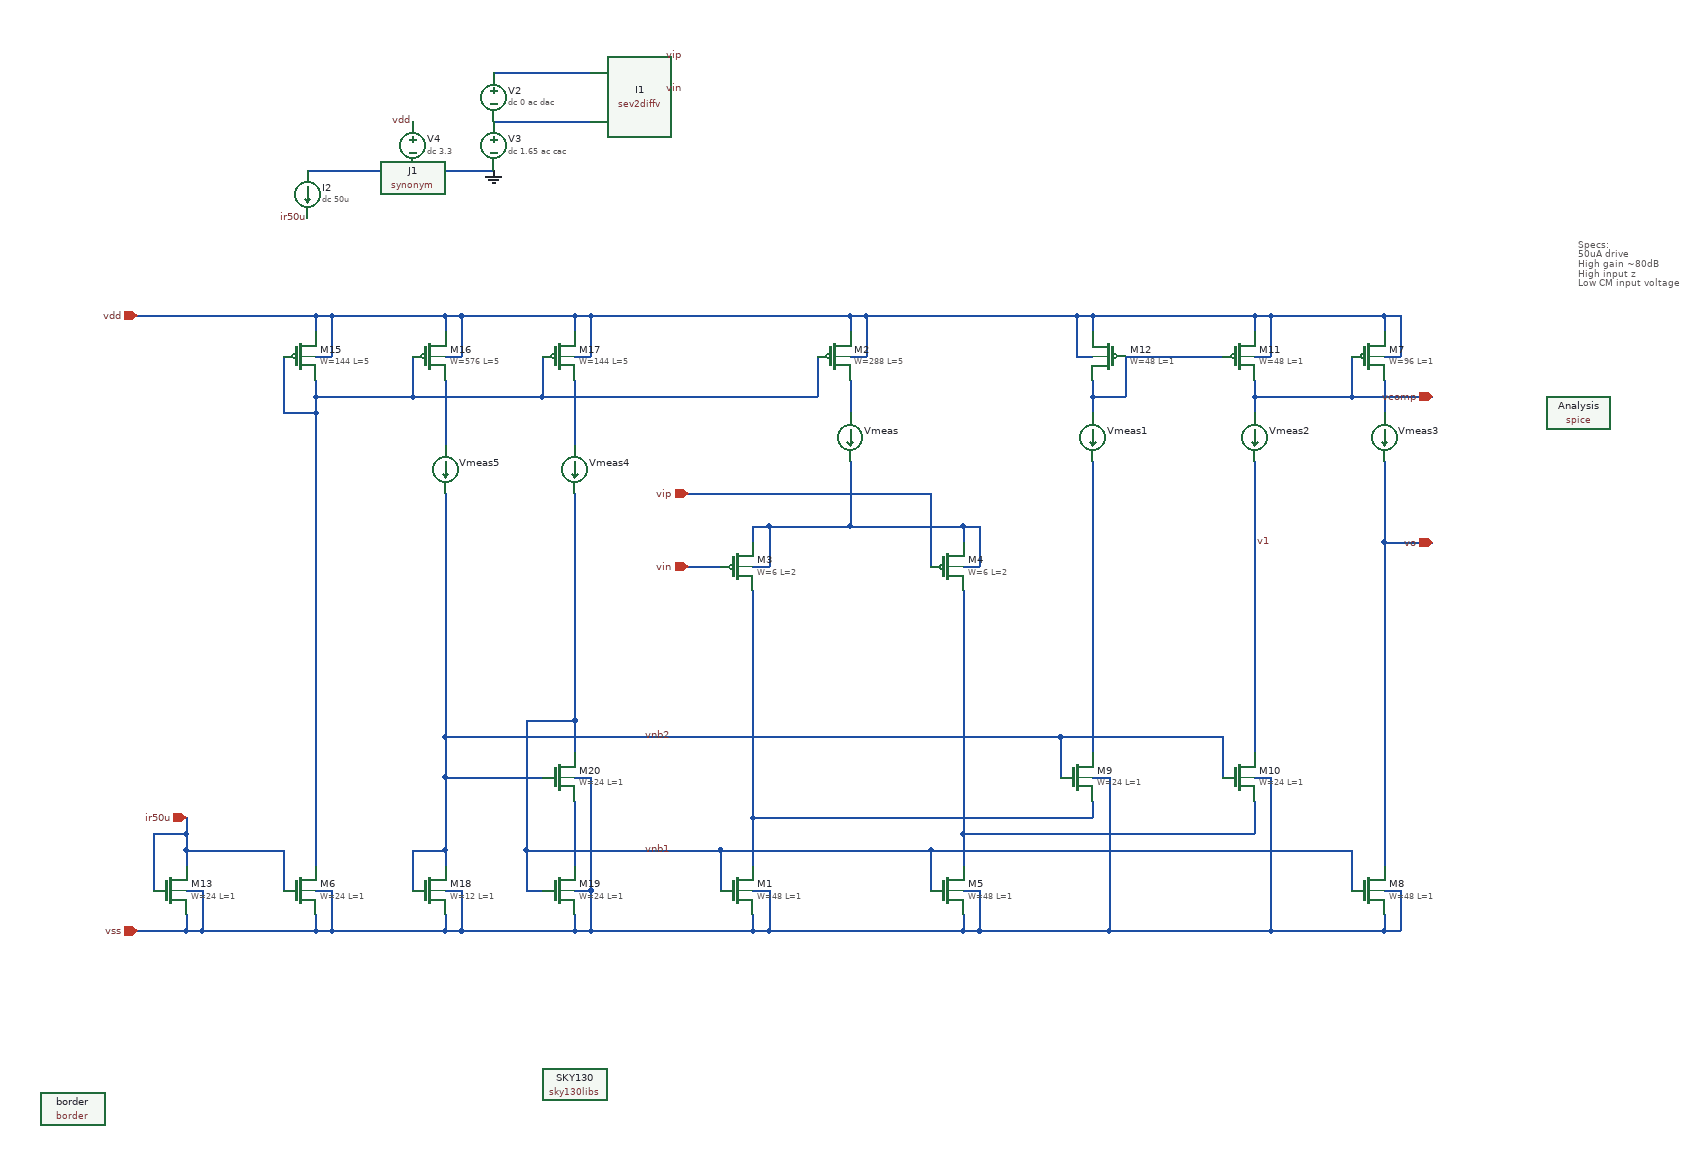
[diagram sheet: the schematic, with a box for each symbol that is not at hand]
v {xschem version=2.9.9 file_version=1.2 }
G {}
K {}
V {}
S {}
E {}
T {Specs:
50uA drive
High gain ~80dB
High input z
Low CM input voltage} 1860 -1080 0 0 0.3 0.3 {}
N 1100 -240 1100 -220 { lab=vss}
N 860 -220 1100 -220 { lab=vss}
N 840 -240 840 -220 { lab=vss}
N 1100 -270 1120 -270 { lab=vss}
N 1120 -270 1120 -220 { lab=vss}
N 1100 -220 1120 -220 { lab=vss}
N 840 -720 840 -700 { lab=#net1}
N 1100 -720 1100 -700 { lab=#net1}
N 960 -930 980 -930 { lab=vdd}
N 980 -980 980 -930 { lab=vdd}
N 960 -980 980 -980 { lab=vdd}
N 960 -980 960 -960 { lab=vdd}
N 920 -930 920 -880 { lab=#net2}
N 760 -670 800 -670 { lab=vin}
N 840 -670 860 -670 { lab=#net1}
N 1100 -670 1120 -670 { lab=#net1}
N 980 -980 1240 -980 { lab=vdd}
N 1620 -700 1680 -700 { lab=vo}
N 520 -1220 640 -1220 { lab=#net3}
N 520 -1280 640 -1280 { lab=#net4}
N 1580 -930 1580 -880 { lab=vcomp}
N 1620 -980 1620 -960 { lab=vdd}
N 1620 -930 1640 -930 { lab=vdd}
N 1640 -980 1640 -930 { lab=vdd}
N 1620 -980 1640 -980 { lab=vdd}
N 1620 -240 1620 -220 { lab=vss}
N 1580 -320 1580 -270 { lab=vnb1}
N 1620 -270 1640 -270 { lab=vss}
N 1640 -270 1640 -220 { lab=vss}
N 1620 -220 1640 -220 { lab=vss}
N 760 -760 1060 -760 { lab=vip}
N 1060 -760 1060 -670 { lab=vip}
N 960 -720 1100 -720 { lab=#net1}
N 290 -1160 520 -1160 { lab=GND}
N 840 -360 840 -300 { lab=#net5}
N 1100 -340 1100 -300 { lab=#net6}
N 1260 -980 1260 -960 { lab=vdd}
N 1240 -980 1260 -980 { lab=vdd}
N 1460 -980 1460 -960 { lab=vdd}
N 1260 -980 1460 -980 { lab=vdd}
N 1240 -930 1260 -930 { lab=vdd}
N 1240 -980 1240 -930 { lab=vdd}
N 1460 -930 1480 -930 { lab=vdd}
N 1480 -980 1480 -930 { lab=vdd}
N 1460 -980 1480 -980 { lab=vdd}
N 1300 -930 1420 -930 { lab=#net7}
N 1260 -410 1280 -410 { lab=vss}
N 1280 -410 1280 -220 { lab=vss}
N 1120 -220 1280 -220 { lab=vss}
N 1460 -410 1480 -410 { lab=vss}
N 1480 -410 1480 -220 { lab=vss}
N 1280 -220 1480 -220 { lab=vss}
N 1260 -380 1260 -360 { lab=#net5}
N 840 -360 1260 -360 { lab=#net5}
N 840 -640 840 -360 { lab=#net5}
N 1460 -380 1460 -340 { lab=#net6}
N 1100 -340 1460 -340 { lab=#net6}
N 1100 -640 1100 -340 { lab=#net6}
N 1420 -460 1420 -410 { lab=vnb2}
N 1220 -460 1420 -460 { lab=vnb2}
N 1220 -460 1220 -410 { lab=vnb2}
N 1060 -320 1060 -270 { lab=vnb1}
N 800 -320 800 -270 { lab=vnb1}
N 1260 -880 1300 -880 { lab=#net7}
N 1260 -900 1260 -880 { lab=#net7}
N 1300 -930 1300 -880 { lab=#net7}
N 1260 -880 1260 -860 { lab=#net7}
N 1260 -800 1260 -440 { lab=#net8}
N 1460 -800 1460 -440 { lab=v1}
N 960 -900 960 -860 { lab=#net9}
N 960 -800 960 -720 { lab=#net1}
N 860 -720 960 -720 { lab=#net1}
N 620 -380 620 -300 { lab=#net10}
N 620 -410 640 -410 { lab=vss}
N 640 -270 640 -220 { lab=vss}
N 620 -220 640 -220 { lab=vss}
N 620 -270 640 -270 { lab=vss}
N 640 -410 640 -270 { lab=vss}
N 620 -240 620 -220 { lab=vss}
N 480 -220 620 -220 { lab=vss}
N 460 -270 480 -270 { lab=vss}
N 480 -270 480 -220 { lab=vss}
N 460 -220 480 -220 { lab=vss}
N 460 -240 460 -220 { lab=vss}
N 560 -270 580 -270 { lab=vnb1}
N 560 -480 620 -480 { lab=vnb1}
N 460 -410 580 -410 { lab=vnb2}
N 460 -320 460 -300 { lab=vnb2}
N 420 -320 420 -270 { lab=vnb2}
N 420 -320 460 -320 { lab=vnb2}
N 460 -410 460 -320 { lab=vnb2}
N 460 -980 460 -960 { lab=vdd}
N 320 -980 460 -980 { lab=vdd}
N 620 -980 620 -960 { lab=vdd}
N 480 -980 620 -980 { lab=vdd}
N 300 -980 300 -960 { lab=vdd}
N 260 -930 260 -860 { lab=#net2}
N 300 -930 320 -930 { lab=vdd}
N 320 -980 320 -930 { lab=vdd}
N 300 -980 320 -980 { lab=vdd}
N 460 -930 480 -930 { lab=vdd}
N 480 -980 480 -930 { lab=vdd}
N 460 -980 480 -980 { lab=vdd}
N 620 -930 640 -930 { lab=vdd}
N 640 -980 640 -930 { lab=vdd}
N 620 -980 640 -980 { lab=vdd}
N 320 -220 460 -220 { lab=vss}
N 260 -860 300 -860 { lab=#net2}
N 300 -880 300 -860 { lab=#net2}
N 420 -880 580 -880 { lab=#net2}
N 580 -930 580 -880 { lab=#net2}
N 300 -900 300 -880 { lab=#net2}
N 420 -930 420 -880 { lab=#net2}
N 300 -880 420 -880 { lab=#net2}
N 460 -900 460 -820 { lab=#net11}
N 620 -900 620 -820 { lab=#net12}
N 620 -760 620 -480 { lab=vnb1}
N 620 -480 620 -440 { lab=vnb1}
N 460 -460 460 -410 { lab=vnb2}
N 560 -320 560 -270 { lab=vnb1}
N 640 -980 960 -980 { lab=vdd}
N 640 -220 840 -220 { lab=vss}
N 800 -320 1060 -320 { lab=vnb1}
N 560 -480 560 -320 { lab=vnb1}
N 460 -460 1220 -460 { lab=vnb2}
N 460 -760 460 -460 { lab=vnb2}
N 580 -880 920 -880 { lab=#net2}
N 560 -320 800 -320 { lab=vnb1}
N 840 -270 860 -270 { lab=vss}
N 860 -270 860 -220 { lab=vss}
N 840 -220 860 -220 { lab=vss}
N 1460 -880 1460 -860 { lab=vcomp}
N 1620 -900 1620 -860 { lab=#net13}
N 1580 -880 1680 -880 { lab=vcomp}
N 860 -720 860 -670 { lab=#net1}
N 840 -720 860 -720 { lab=#net1}
N 1120 -720 1120 -670 { lab=#net1}
N 1100 -720 1120 -720 { lab=#net1}
N 1620 -700 1620 -300 { lab=vo}
N 1060 -320 1580 -320 { lab=vnb1}
N 1480 -980 1620 -980 { lab=vdd}
N 1480 -220 1620 -220 { lab=vss}
N 300 -860 300 -300 { lab=#net2}
N 300 -270 320 -270 { lab=vss}
N 320 -270 320 -220 { lab=vss}
N 300 -220 320 -220 { lab=vss}
N 300 -240 300 -220 { lab=vss}
N 160 -220 300 -220 { lab=vss}
N 140 -240 140 -220 { lab=vss}
N 140 -270 160 -270 { lab=vss}
N 160 -270 160 -220 { lab=vss}
N 140 -220 160 -220 { lab=vss}
N 100 -340 100 -270 { lab=ir50u}
N 100 -340 140 -340 { lab=ir50u}
N 140 -320 140 -300 { lab=ir50u}
N 140 -320 260 -320 { lab=ir50u}
N 260 -320 260 -270 { lab=ir50u}
N 140 -340 140 -320 { lab=ir50u}
N 140 -360 140 -340 { lab=ir50u}
N 80 -980 300 -980 { lab=vdd}
N 80 -220 140 -220 { lab=vss}
N 1460 -900 1460 -880 { lab=vcomp}
N 1460 -880 1580 -880 { lab=vcomp}
N 1620 -800 1620 -700 { lab=vo}
C {common/spice.sym} 1860 -860 0 0 {name=Analysis
tclcommand="xschem netlist; xschem simulate"
only_toplevel=true
value="
.param mc_mm_switch=0

.parameter width=1
.parameter cac=0
.parameter dac=\{1-cac\}

.control

save all

*dc srcnam vstart vstop vincr [src2 start2 stop2 incr2]
*ac dec nd fstart fstop
*tran tstep tstop <tstart <tmax>> <uic>

op
let vgs=\{ir-vdd\}
let itail=@m.xm2.msky130_fd_pr__pfet_g5v0d10v5[id]
let gds2=@m.xm2.msky130_fd_pr__pfet_g5v0d10v5[gds]
let gds4=@m.xm4.msky130_fd_pr__pfet_g5v0d10v5[gds]
let gds5=@m.xm5.msky130_fd_pr__nfet_g5v0d10v5[gds]

dc v2 -2m 2m 1u
plot vo

ac dec 1000 1 1gig
let voph = 180/pi*vp(vo)
let v1ph = 180/pi*vp(v1)
meas ac ac_pm find voph when vdb(vo)=0
let ac_pm=180+ac_pm
print ac_pm
plot vdb(vo) voph
*plot vdb(v1) v1ph

op
write bgr_amp_bak.raw

.endc
"
}
C {sky130_fd_pr/nfet_g5v0d10v5.sym} 820 -270 0 0 {name=M1
L=1
W=48
nf=8
mult=1
ad="'int((nf+1)/2) * W/nf * 0.29'" 
pd="'2*int((nf+1)/2) * (W/nf + 0.29)'"
as="'int((nf+2)/2) * W/nf * 0.29'" 
ps="'2*int((nf+2)/2) * (W/nf + 0.29)'"
nrd="'0.29 / W'" nrs="'0.29 / W'"
sa=0 sb=0 sd=0
model=nfet_g5v0d10v5
spiceprefix=X
}
C {sky130_fd_pr/pfet_g5v0d10v5.sym} 940 -930 0 0 {name=M2
L=5
W=288
nf=12
mult=1
ad="'int((nf+1)/2) * W/nf * 0.29'" 
pd="'2*int((nf+1)/2) * (W/nf + 0.29)'"
as="'int((nf+2)/2) * W/nf * 0.29'" 
ps="'2*int((nf+2)/2) * (W/nf + 0.29)'"
nrd="'0.29 / W'" nrs="'0.29 / W'"
sa=0 sb=0 sd=0
model=pfet_g5v0d10v5
spiceprefix=X
}
C {sky130_fd_pr/pfet_g5v0d10v5.sym} 820 -670 0 0 {name=M3
L=2
W=6
nf=1
mult=25
ad="'int((nf+1)/2) * W/nf * 0.29'" 
pd="'2*int((nf+1)/2) * (W/nf + 0.29)'"
as="'int((nf+2)/2) * W/nf * 0.29'" 
ps="'2*int((nf+2)/2) * (W/nf + 0.29)'"
nrd="'0.29 / W'" nrs="'0.29 / W'"
sa=0 sb=0 sd=0
model=pfet_g5v0d10v5
spiceprefix=X
}
C {sky130_fd_pr/pfet_g5v0d10v5.sym} 1080 -670 0 0 {name=M4
L=2
W=6
nf=1
mult=25
ad="'int((nf+1)/2) * W/nf * 0.29'" 
pd="'2*int((nf+1)/2) * (W/nf + 0.29)'"
as="'int((nf+2)/2) * W/nf * 0.29'" 
ps="'2*int((nf+2)/2) * (W/nf + 0.29)'"
nrd="'0.29 / W'" nrs="'0.29 / W'"
sa=0 sb=0 sd=0
model=pfet_g5v0d10v5
spiceprefix=X
}
C {sky130_fd_pr/nfet_g5v0d10v5.sym} 1080 -270 0 0 {name=M5
L=1
W=48
nf=8
mult=1
ad="'int((nf+1)/2) * W/nf * 0.29'" 
pd="'2*int((nf+1)/2) * (W/nf + 0.29)'"
as="'int((nf+2)/2) * W/nf * 0.29'" 
ps="'2*int((nf+2)/2) * (W/nf + 0.29)'"
nrd="'0.29 / W'" nrs="'0.29 / W'"
sa=0 sb=0 sd=0
model=nfet_g5v0d10v5
spiceprefix=X
}
C {devices/iopin.sym} 80 -980 2 0 {name=p7 lab=vdd}
C {devices/iopin.sym} 80 -220 2 0 {name=p1 lab=vss}
C {devices/gnd.sym} 520 -1160 0 0 {name=l1 lab=GND}
C {sev2diffv.sym} 680 -1280 0 0 {
name=I1
spiceprefix=X
model=sev2diffv
gain=1
}
C {vsource.sym} 520 -1250 0 0 {
name=V2
value="dc 0 ac dac"
}
C {vsource.sym} 520 -1190 0 0 {
name=V3
value="dc 1.65 ac cac"
}
C {devices/lab_pin.sym} 420 -1220 1 0 {name=l2 sig_type=std_logic lab=vdd}
C {devices/lab_pin.sym} 420 -1140 3 0 {name=l3 sig_type=std_logic lab=vss}
C {vsource.sym} 420 -1190 0 0 {
name=V4
value="dc 3.3"
}
C {devices/lab_pin.sym} 730 -1300 2 0 {name=l4 sig_type=std_logic lab=vip}
C {devices/lab_pin.sym} 730 -1260 2 0 {name=l5 sig_type=std_logic lab=vin}
C {isource.sym} 290 -1130 0 0 {
name=I2
value="dc 50u"
}
C {devices/lab_pin.sym} 290 -1100 3 0 {name=l6 sig_type=std_logic lab=ir50u}
C {sky130_fd_pr/pfet_g5v0d10v5.sym} 1600 -930 0 0 {name=M7
L=1
W=96
nf=16
mult=1
ad="'int((nf+1)/2) * W/nf * 0.29'" 
pd="'2*int((nf+1)/2) * (W/nf + 0.29)'"
as="'int((nf+2)/2) * W/nf * 0.29'" 
ps="'2*int((nf+2)/2) * (W/nf + 0.29)'"
nrd="'0.29 / W'" nrs="'0.29 / W'"
sa=0 sb=0 sd=0
model=pfet_g5v0d10v5
spiceprefix=X
}
C {sky130_fd_pr/nfet_g5v0d10v5.sym} 1600 -270 0 0 {name=M8
L=1
W=48
nf=8
mult=1
ad="'int((nf+1)/2) * W/nf * 0.29'" 
pd="'2*int((nf+1)/2) * (W/nf + 0.29)'"
as="'int((nf+2)/2) * W/nf * 0.29'" 
ps="'2*int((nf+2)/2) * (W/nf + 0.29)'"
nrd="'0.29 / W'" nrs="'0.29 / W'"
sa=0 sb=0 sd=0
model=nfet_g5v0d10v5
spiceprefix=X
}
C {synonym.sym} 420 -1150 0 0 {
name=J1
}
C {sky130_fd_pr/nfet_g5v0d10v5.sym} 1240 -410 0 0 {name=M9
L=1
W=24
nf=4
mult=1
ad="'int((nf+1)/2) * W/nf * 0.29'" 
pd="'2*int((nf+1)/2) * (W/nf + 0.29)'"
as="'int((nf+2)/2) * W/nf * 0.29'" 
ps="'2*int((nf+2)/2) * (W/nf + 0.29)'"
nrd="'0.29 / W'" nrs="'0.29 / W'"
sa=0 sb=0 sd=0
model=nfet_g5v0d10v5
spiceprefix=X
}
C {sky130_fd_pr/nfet_g5v0d10v5.sym} 1440 -410 0 0 {name=M10
L=1
W=24
nf=4
mult=1
ad="'int((nf+1)/2) * W/nf * 0.29'" 
pd="'2*int((nf+1)/2) * (W/nf + 0.29)'"
as="'int((nf+2)/2) * W/nf * 0.29'" 
ps="'2*int((nf+2)/2) * (W/nf + 0.29)'"
nrd="'0.29 / W'" nrs="'0.29 / W'"
sa=0 sb=0 sd=0
model=nfet_g5v0d10v5
spiceprefix=X
}
C {sky130_fd_pr/pfet_g5v0d10v5.sym} 1440 -930 0 0 {name=M11
L=1
W=48
nf=8
mult=1
ad="'int((nf+1)/2) * W/nf * 0.29'" 
pd="'2*int((nf+1)/2) * (W/nf + 0.29)'"
as="'int((nf+2)/2) * W/nf * 0.29'" 
ps="'2*int((nf+2)/2) * (W/nf + 0.29)'"
nrd="'0.29 / W'" nrs="'0.29 / W'"
sa=0 sb=0 sd=0
model=pfet_g5v0d10v5
spiceprefix=X
}
C {sky130_fd_pr/pfet_g5v0d10v5.sym} 1280 -930 0 1 {name=M12
L=1
W=48
nf=8
mult=1
ad="'int((nf+1)/2) * W/nf * 0.29'" 
pd="'2*int((nf+1)/2) * (W/nf + 0.29)'"
as="'int((nf+2)/2) * W/nf * 0.29'" 
ps="'2*int((nf+2)/2) * (W/nf + 0.29)'"
nrd="'0.29 / W'" nrs="'0.29 / W'"
sa=0 sb=0 sd=0
model=pfet_g5v0d10v5
spiceprefix=X
}
C {devices/spice_probe.sym} 740 -320 0 0 {name=p2 attrs="" voltage=0.9932}
C {devices/spice_probe.sym} 740 -460 0 0 {name=p8 attrs="" voltage=1.371}
C {devices/spice_probe.sym} 840 -520 0 0 {name=p9 attrs="" voltage=0.2887}
C {devices/spice_probe.sym} 1100 -520 0 0 {name=p10 attrs="" voltage=0.2887}
C {devices/spice_probe.sym} 1260 -600 0 0 {name=p11 attrs="" voltage=2.091}
C {devices/spice_probe.sym} 1460 -600 0 0 {name=p12 attrs="" voltage=2.091}
C {devices/spice_probe.sym} 760 -880 0 0 {name=p13 attrs="" voltage=1.969}
C {devices/launcher.sym} 920 -1090 0 0 {name=h1
descr=Backannotate
tclcommand="ngspice::annotate"}
C {common/border.sym} 0 0 0 0 {design_name="Bandgap Ref Amp"
revision="00"
author="Tom"
name="border"
}
C {common/sky130libs.sym} 620 -30 0 0 {name=SKY130
only_toplevel=true
value="
.include \\"\\\\$::ANALOG_LIB\\\\\\"
.include \\"\\\\$::PDK_FD_SC_HD\\\\\\"
.lib \\"\\\\$::PDK_FD_PR\\\\ tt\\"
.option wnflag=1
"
}
C {devices/ammeter.sym} 960 -830 0 0 {name=Vmeas current=1.0279e-04}
C {devices/ammeter.sym} 1260 -830 0 0 {name=Vmeas1 current=5.5130e-05}
C {devices/ammeter.sym} 1460 -830 0 0 {name=Vmeas2 current=5.5130e-05}
C {devices/ammeter.sym} 1620 -830 0 0 {name=Vmeas3 current=1.1789e-04}
C {devices/lab_pin.sym} 740 -460 3 0 {name=l7 sig_type=std_logic lab=vnb2}
C {devices/lab_pin.sym} 740 -320 3 0 {name=l8 sig_type=std_logic lab=vnb1}
C {devices/spice_probe.sym} 880 -720 0 0 {name=p14 attrs="" voltage=2.829}
C {sky130_fd_pr/pfet_g5v0d10v5.sym} 280 -930 0 0 {name=M15
L=5
W=144
nf=6
mult=1
ad="'int((nf+1)/2) * W/nf * 0.29'" 
pd="'2*int((nf+1)/2) * (W/nf + 0.29)'"
as="'int((nf+2)/2) * W/nf * 0.29'" 
ps="'2*int((nf+2)/2) * (W/nf + 0.29)'"
nrd="'0.29 / W'" nrs="'0.29 / W'"
sa=0 sb=0 sd=0
model=pfet_g5v0d10v5
spiceprefix=X
}
C {sky130_fd_pr/pfet_g5v0d10v5.sym} 440 -930 0 0 {name=M16
L=5
W=576
nf=24
mult=1
ad="'int((nf+1)/2) * W/nf * 0.29'" 
pd="'2*int((nf+1)/2) * (W/nf + 0.29)'"
as="'int((nf+2)/2) * W/nf * 0.29'" 
ps="'2*int((nf+2)/2) * (W/nf + 0.29)'"
nrd="'0.29 / W'" nrs="'0.29 / W'"
sa=0 sb=0 sd=0
model=pfet_g5v0d10v5
spiceprefix=X
}
C {sky130_fd_pr/pfet_g5v0d10v5.sym} 600 -930 0 0 {name=M17
L=5
W=144
nf=6
mult=1
ad="'int((nf+1)/2) * W/nf * 0.29'" 
pd="'2*int((nf+1)/2) * (W/nf + 0.29)'"
as="'int((nf+2)/2) * W/nf * 0.29'" 
ps="'2*int((nf+2)/2) * (W/nf + 0.29)'"
nrd="'0.29 / W'" nrs="'0.29 / W'"
sa=0 sb=0 sd=0
model=pfet_g5v0d10v5
spiceprefix=X
}
C {sky130_fd_pr/nfet_g5v0d10v5.sym} 440 -270 0 0 {name=M18
L=1
W=12
nf=2
mult=1
ad="'int((nf+1)/2) * W/nf * 0.29'" 
pd="'2*int((nf+1)/2) * (W/nf + 0.29)'"
as="'int((nf+2)/2) * W/nf * 0.29'" 
ps="'2*int((nf+2)/2) * (W/nf + 0.29)'"
nrd="'0.29 / W'" nrs="'0.29 / W'"
sa=0 sb=0 sd=0
model=nfet_g5v0d10v5
spiceprefix=X
}
C {sky130_fd_pr/nfet_g5v0d10v5.sym} 600 -270 0 0 {name=M19
L=1
W=24
nf=4
mult=1
ad="'int((nf+1)/2) * W/nf * 0.29'" 
pd="'2*int((nf+1)/2) * (W/nf + 0.29)'"
as="'int((nf+2)/2) * W/nf * 0.29'" 
ps="'2*int((nf+2)/2) * (W/nf + 0.29)'"
nrd="'0.29 / W'" nrs="'0.29 / W'"
sa=0 sb=0 sd=0
model=nfet_g5v0d10v5
spiceprefix=X
}
C {sky130_fd_pr/nfet_g5v0d10v5.sym} 600 -410 0 0 {name=M20
L=1
W=24
nf=4
mult=1
ad="'int((nf+1)/2) * W/nf * 0.29'" 
pd="'2*int((nf+1)/2) * (W/nf + 0.29)'"
as="'int((nf+2)/2) * W/nf * 0.29'" 
ps="'2*int((nf+2)/2) * (W/nf + 0.29)'"
nrd="'0.29 / W'" nrs="'0.29 / W'"
sa=0 sb=0 sd=0
model=nfet_g5v0d10v5
spiceprefix=X
}
C {devices/ammeter.sym} 620 -790 0 0 {name=Vmeas4 current=5.3207e-05}
C {devices/ammeter.sym} 460 -790 0 0 {name=Vmeas5 current=2.1168e-04}
C {devices/spice_probe.sym} 620 -530 0 0 {name=p15 attrs="" voltage=0.9932}
C {devices/spice_probe.sym} 520 -880 0 0 {name=p17 attrs="" voltage=1.969}
C {devices/spice_probe.sym} 620 -340 0 0 {name=p18 attrs="" voltage=0.2865}
C {devices/lab_pin.sym} 1460 -700 2 0 {name=l9 sig_type=std_logic lab=v1}
C {devices/iopin.sym} 1680 -880 0 0 {name=p19 lab=vcomp}
C {devices/iopin.sym} 760 -760 2 0 {name=p20 lab=vip}
C {devices/iopin.sym} 760 -670 2 0 {name=p21 lab=vin}
C {devices/iopin.sym} 1680 -700 0 0 {name=p22 lab=vo}
C {devices/iopin.sym} 140 -360 3 0 {name=p3 lab=ir50u}
C {sky130_fd_pr/nfet_g5v0d10v5.sym} 280 -270 0 0 {name=M6
L=1
W=24
nf=4
mult=1
ad="'int((nf+1)/2) * W/nf * 0.29'" 
pd="'2*int((nf+1)/2) * (W/nf + 0.29)'"
as="'int((nf+2)/2) * W/nf * 0.29'" 
ps="'2*int((nf+2)/2) * (W/nf + 0.29)'"
nrd="'0.29 / W'" nrs="'0.29 / W'"
sa=0 sb=0 sd=0
model=nfet_g5v0d10v5
spiceprefix=X
}
C {sky130_fd_pr/nfet_g5v0d10v5.sym} 120 -270 0 0 {name=M13
L=1
W=24
nf=4
mult=1
ad="'int((nf+1)/2) * W/nf * 0.29'" 
pd="'2*int((nf+1)/2) * (W/nf + 0.29)'"
as="'int((nf+2)/2) * W/nf * 0.29'" 
ps="'2*int((nf+2)/2) * (W/nf + 0.29)'"
nrd="'0.29 / W'" nrs="'0.29 / W'"
sa=0 sb=0 sd=0
model=nfet_g5v0d10v5
spiceprefix=X
}
C {devices/spice_probe.sym} 180 -320 0 0 {name=p4 attrs="" voltage=0.9755}
